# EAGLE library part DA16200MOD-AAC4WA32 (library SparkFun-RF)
Check prices

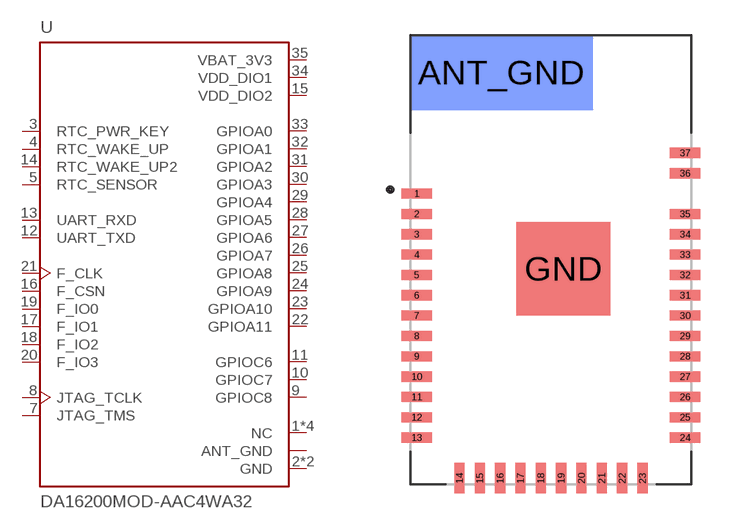
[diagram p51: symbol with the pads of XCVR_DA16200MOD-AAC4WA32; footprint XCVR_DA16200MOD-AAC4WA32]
Designator prefix U

## DA16200MOD-AAC4WA32 (PROD_ID: IC-16179; VALUE: DA16200MOD)  [XCVR_DA16200MOD-AAC4WA32]
1  NC  nc
2  GND  pwr
3  RTC_PWR_KEY  in
4  RTC_WAKE_UP  in
5  RTC_SENSOR  out
6  NC  nc
7  JTAG_TMS
8  JTAG_TCLK
9  GPIOC8
10  GPIOC7
11  GPIOC6
12  UART_TXD  out
13  UART_RXD  in
14  RTC_WAKE_UP2  in
15  VDD_DIO2  pwr
16  F_CSN
17  F_IO1
18  F_IO2
19  F_IO0
20  F_IO3
21  F_CLK
22  GPIOA11
23  GPIOA10
24  GPIOA9
25  GPIOA8
26  GPIOA7
27  GPIOA6
28  GPIOA5
29  GPIOA4
30  GPIOA3
31  GPIOA2
32  GPIOA1
33  GPIOA0
34  VDD_DIO1  pwr
35  VBAT_3V3  pwr
36  NC  nc
37  NC  nc
ANT_GND  ANT_GND  pwr
GND  GND  pwr

## Footprint XCVR_DA16200MOD-AAC4WA32 (pad centres in mm)
smd 1.5 x 0.5: 1 -6.6,3.25; 2 -6.6,2.25; 3 -6.6,1.25; 4 -6.6,0.25; 5 -6.6,-0.75; 6 -6.6,-1.75; 7 -6.6,-2.75; 8 -6.6,-3.75; 9 -6.6,-4.75; 10 -6.6,-5.75; 11 -6.6,-6.75; 12 -6.6,-7.75; 13 -6.6,-8.75; 24 6.6,-8.75; 25 6.6,-7.75; 26 6.6,-6.75; 27 6.6,-5.75; 28 6.6,-4.75; 29 6.6,-3.75; 30 6.6,-2.75; 31 6.6,-1.75; 32 6.6,-0.75; 33 6.6,0.25; 34 6.6,1.25; 35 6.6,2.25; 36 6.6,4.25; 37 6.6,5.25
smd 0.5 x 1.5: 14 -4.5,-10.75; 15 -3.5,-10.75; 16 -2.5,-10.75; 17 -1.5,-10.75; 18 -0.5,-10.75; 19 0.5,-10.75; 20 1.5,-10.75; 21 2.5,-10.75; 22 3.5,-10.75; 23 4.5,-10.75
smd 9 x 3.7 bottom: ANT_GND -2.45,9.2
smd 4.6 x 4.6: GND 0.61,-0.45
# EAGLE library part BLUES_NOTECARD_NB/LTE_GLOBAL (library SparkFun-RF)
Blues Wireless NoteCard NB/LTE - Global As an embeddable device-to-cloud data pump, the Notecard eliminates all complexity and friction that exists with existing IoT solutions. It enables development and rapid iteration of production-quality secure cellular or Wi-Fi IoT solutions at an extremely low, fixed cost. With as little as two lines of code on the controlling MCU, and with no external libraries or dependencies, data can be sent from device to cloud.

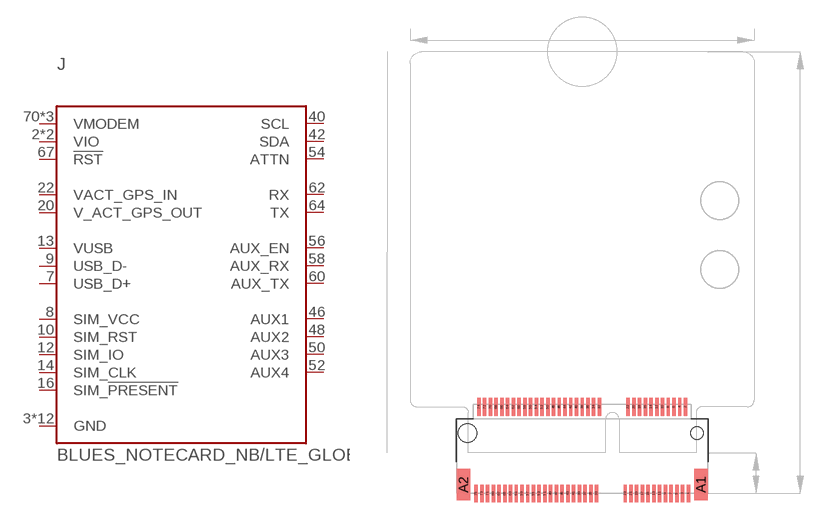
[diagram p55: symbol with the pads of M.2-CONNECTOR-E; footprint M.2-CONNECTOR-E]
Designator prefix J

## BLUES_NOTECARD_NB/LTE_GLOBAL (PROD_ID: CONN-14877; VALUE: Blues Notecard)  [M.2-CONNECTOR-E]
2  VIO
3  GND
4  VIO
5  GND
6  GND
7  USB_D+
8  SIM_VCC
9  USB_D-
10  SIM_RST
11  GND
12  SIM_IO
13  VUSB
14  SIM_CLK
16  SIM_!PRESENT!
18  GND
20  V_ACT_GPS_OUT
22  VACT_GPS_IN
33  GND
39  GND
40  SCL
42  SDA
45  GND
46  AUX1
48  AUX2
50  AUX3
51  GND
52  AUX4
54  ATTN
56  AUX_EN
57  GND
58  AUX_RX
60  AUX_TX
62  RX
64  TX
67  !RST!
70  VMODEM
71  GND
72  VMODEM
73  GND
74  VMODEM

## Footprint M.2-CONNECTOR-E (pad centres in mm)
smd 0.3 x 1.55: 1 9.25,-5.275; 2 9,2.275; 3 8.75,-5.275; 4 8.5,2.275; 5 8.25,-5.275; 6 8,2.275; 7 7.75,-5.275; 8 7.5,2.275; 9 7.25,-5.275; 10 7,2.275; 11 6.75,-5.275; 12 6.5,2.275; 13 6.25,-5.275; 14 6,2.275; 15 5.75,-5.275; 16 5.5,2.275; 17 5.25,-5.275; 18 5,2.275; 19 4.75,-5.275; 20 4.5,2.275; 21 4.25,-5.275; 22 4,2.275; 23 3.75,-5.275; 32 1.5,2.275; 33 1.25,-5.275; 34 1,2.275; 35 0.75,-5.275; 36 0.5,2.275; 37 0.25,-5.275; 38 0,2.275; 39 -0.25,-5.275; 40 -0.5,2.275; 41 -0.75,-5.275; 42 -1,2.275; 43 -1.25,-5.275; 44 -1.5,2.275; 45 -1.75,-5.275; 46 -2,2.275; 47 -2.25,-5.275; 48 -2.5,2.275; 49 -2.75,-5.275; 50 -3,2.275; 51 -3.25,-5.275; 52 -3.5,2.275; 53 -3.75,-5.275; 54 -4,2.275; 55 -4.25,-5.275; 56 -4.5,2.275; 57 -4.75,-5.275; 58 -5,2.275; 59 -5.25,-5.275; 60 -5.5,2.275; 61 -5.75,-5.275; 62 -6,2.275; 63 -6.25,-5.275; 64 -6.5,2.275; 65 -6.75,-5.275; 66 -7,2.275; 67 -7.25,-5.275; 68 -7.5,2.275; 69 -7.75,-5.275; 70 -8,2.275; 71 -8.25,-5.275; 72 -8.5,2.275; 73 -8.75,-5.275; 74 -9,2.275; 75 -9.25,-5.275
smd 1.2 x 2.75: A1 10.35,-4.5; A2 -10.35,-4.5
hole 1.1 at 10,0
hole 1.6 at -10,0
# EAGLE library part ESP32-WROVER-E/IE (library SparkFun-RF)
ESP32-WROVER-E/IE ESP32-WROVER-E uses the onboard antenna. ESP32-WROVER-IE has a u.FL antenna connector, but is otherwise the same as the -E. N16R8 has 16M Flash, 8M PSRAM

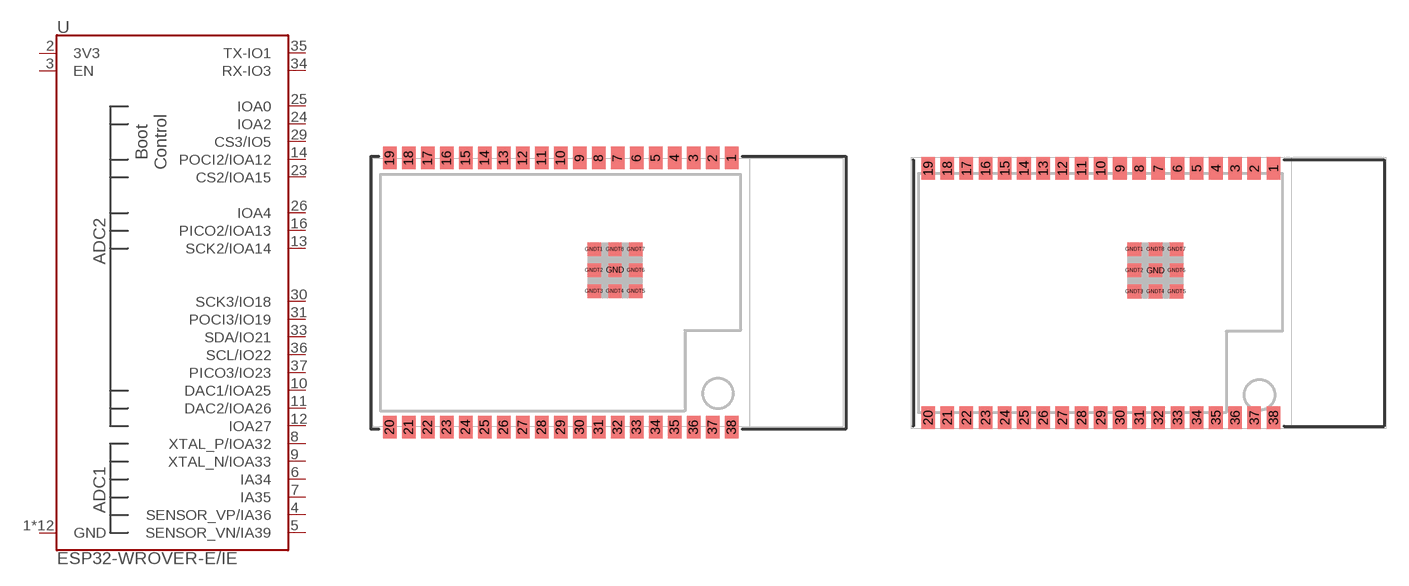
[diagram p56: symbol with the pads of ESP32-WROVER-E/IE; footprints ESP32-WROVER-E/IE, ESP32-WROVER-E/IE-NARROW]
Designator prefix U

## ESP32-WROVER-E/IE_IE-N16R8 (PROD_ID: IC-19265)  [ESP32-WROVER-E/IE]
1  GND
2  3V3
3  EN
4  SENSOR_VP/IA36
5  SENSOR_VN/IA39
6  IA34
7  IA35
8  XTAL_P/IOA32
9  XTAL_N/IOA33
10  DAC1/IOA25
11  DAC2/IOA26
12  IOA27
13  SCK2/IOA14
14  POCI2/IOA12
15  GND
16  PICO2/IOA13
23  CS2/IOA15
24  IOA2
25  IOA0
26  IOA4
29  CS3/IO5
30  SCK3/IO18
31  POCI3/IO19
33  SDA/IO21
34  RX-IO3
35  TX-IO1
36  SCL/IO22
37  PICO3/IO23
38  GND
GND  GND
GNDT1  GND
GNDT2  GND
GNDT3  GND
GNDT4  GND
GNDT5  GND
GNDT6  GND
GNDT7  GND
GNDT8  GND

## ESP32-WROVER-E/IE_IE-N16R8_NARROW (PROD_ID: IC-19265)  [ESP32-WROVER-E/IE-NARROW]
Pads as for ESP32-WROVER-E/IE

## Footprint ESP32-WROVER-E/IE (pad centres in mm)
ESP32-WROVER-E/IE ESP32-WROVER-E uses the onboard antenna. ESP32-WROVER-IE has a u.FL antenna connector, but is otherwise the same size as the -E.
smd 0.9 x 1.5: 1 7.8,9; 2 6.53,9; 3 5.26,9; 4 3.99,9; 5 2.72,9; 6 1.45,9; 7 0.18,9; 8 -1.09,9; 9 -2.36,9; 10 -3.63,9; 11 -4.9,9; 12 -6.17,9; 13 -7.44,9; 14 -8.71,9; 15 -9.98,9; 16 -11.25,9; 17 -12.52,9; 18 -13.79,9; 19 -15.06,9; 20 -15.06,-9; 21 -13.79,-9; 22 -12.52,-9; 23 -11.25,-9; 24 -9.98,-9; 25 -8.71,-9; 26 -7.44,-9; 27 -6.17,-9; 28 -4.9,-9; 29 -3.63,-9; 30 -2.36,-9; 31 -1.09,-9; 32 0.18,-9; 33 1.45,-9; 34 2.72,-9; 35 3.99,-9; 36 5.26,-9; 37 6.53,-9; 38 7.8,-9
smd 0.9 x 0.9: GND 0,1.5; GNDT1 -1.4,2.9; GNDT2 -1.4,1.5; GNDT3 -1.4,0.1; GNDT4 0,0.1; GNDT5 1.4,0.1; GNDT6 1.4,1.5; GNDT7 1.4,2.9; GNDT8 0,2.9

## Footprint ESP32-WROVER-E/IE-NARROW (pad centres in mm)
ESP32-WROVER-E/IE ESP32-WROVER-E uses the onboard antenna. ESP32-WROVER-IE has a u.FL antenna connector, but is otherwise the same size as the -E.
smd 0.9 x 1.5: 1 7.8,8.25; 2 6.53,8.25; 3 5.26,8.25; 4 3.99,8.25; 5 2.72,8.25; 6 1.45,8.25; 7 0.18,8.25; 8 -1.09,8.25; 9 -2.36,8.25; 10 -3.63,8.25; 11 -4.9,8.25; 12 -6.17,8.25; 13 -7.44,8.25; 14 -8.71,8.25; 15 -9.98,8.25; 16 -11.25,8.25; 17 -12.52,8.25; 18 -13.79,8.25; 19 -15.06,8.25; 20 -15.06,-8.25; 21 -13.79,-8.25; 22 -12.52,-8.25; 23 -11.25,-8.25; 24 -9.98,-8.25; 25 -8.71,-8.25; 26 -7.44,-8.25; 27 -6.17,-8.25; 28 -4.9,-8.25; 29 -3.63,-8.25; 30 -2.36,-8.25; 31 -1.09,-8.25; 32 0.18,-8.25; 33 1.45,-8.25; 34 2.72,-8.25; 35 3.99,-8.25; 36 5.26,-8.25; 37 6.53,-8.25; 38 7.8,-8.25
smd 0.9 x 0.9: GND 0,1.5; GNDT1 -1.4,2.9; GNDT2 -1.4,1.5; GNDT3 -1.4,0.1; GNDT4 0,0.1; GNDT5 1.4,0.1; GNDT6 1.4,1.5; GNDT7 1.4,2.9; GNDT8 0,2.9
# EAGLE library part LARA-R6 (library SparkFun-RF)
u-blox LARA-R6 single or multi-mode LTE Cat 1 modules

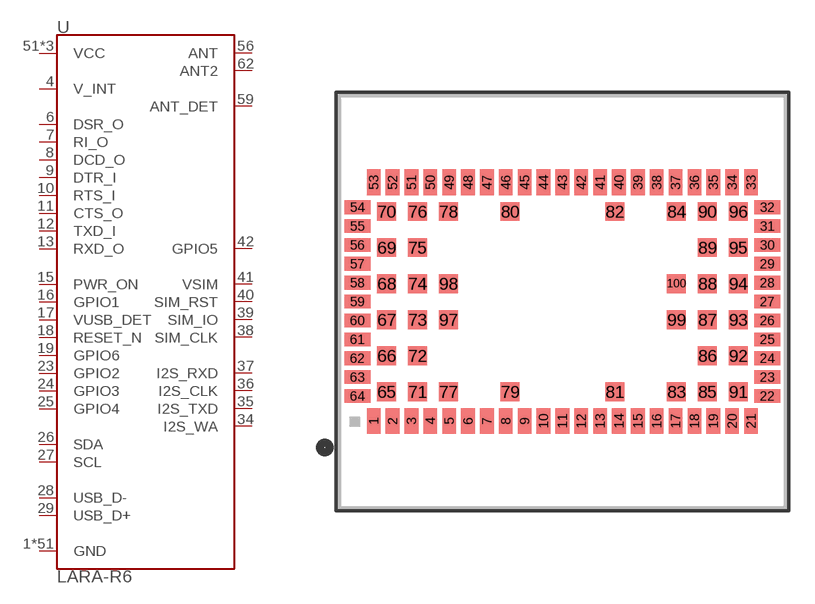
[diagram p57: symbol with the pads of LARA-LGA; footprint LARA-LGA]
Designator prefix U

## LARA-R6_R6001D_GLOBAL_DATA-ONLY (PROD_ID: IC-16661; VALUE: LARA-R6001D)  [LARA-LGA]
1  GND  pwr
3  GND  pwr
4  V_INT  out
5  GND  pwr
6  DSR_O  out
7  RI_O  out
8  DCD_O  out
9  DTR_I  in
10  RTS_I  in
11  CTS_O  out
12  TXD_I  in
13  RXD_O  out
14  GND  pwr
15  PWR_ON  in
16  GPIO1
17  VUSB_DET  in
18  RESET_N  in
19  GPIO6
20  GND  pwr
21  GND  pwr
22  GND  pwr
23  GPIO2
24  GPIO3
25  GPIO4
26  SDA
27  SCL
28  USB_D-
29  USB_D+
30  GND  pwr
32  GND  pwr
34  I2S_WA  out
35  I2S_TXD  out
36  I2S_CLK  out
37  I2S_RXD  in
38  SIM_CLK  out
39  SIM_IO
40  SIM_RST  out
41  VSIM  out
42  GPIO5
43  GND  pwr
50  GND  pwr
51  VCC  pwr
52  VCC  pwr
53  VCC  pwr
54  GND  pwr
55  GND  pwr
56  ANT
57  GND  pwr
58  GND  pwr
59  ANT_DET  in
60  GND  pwr
61  GND  pwr
62  ANT2
63  GND  pwr
64  GND  pwr
65  GND  pwr
66  GND  pwr
67  GND  pwr
68  GND  pwr
69  GND  pwr
70  GND  pwr
71  GND  pwr
72  GND  pwr
73  GND  pwr
74  GND  pwr
75  GND  pwr
76  GND  pwr
77  GND  pwr
78  GND  pwr
79  GND  pwr
80  GND  pwr
81  GND  pwr
82  GND  pwr
83  GND  pwr
84  GND  pwr
85  GND  pwr
86  GND  pwr
87  GND  pwr
88  GND  pwr
89  GND  pwr
90  GND  pwr
91  GND  pwr
92  GND  pwr
93  GND  pwr
94  GND  pwr
95  GND  pwr
96  GND  pwr

## LARA-R6_R6001_GLOBAL (PROD_ID: IC-17186; VALUE: LARA-R6001)  [LARA-LGA]
Pads as for LARA-LGA

## LARA-R6_R6401_USA (PROD_ID: IC-16756; VALUE: LARA-R6401)  [LARA-LGA]
Pads as for LARA-LGA

## Footprint LARA-LGA (pad centres in mm)
ublox LARA LGA form factor Miniature cellular modem package. Common form factor for many ublox cellular modules, including LARA-R6 series. Dimensions: 26.0 x 24.0 mm Pins: 100 Pitch: 1.1mm As per the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
smd 0.8 x 1.5: 1 -11,-6.95; 2 -9.9,-6.95; 3 -8.8,-6.95; 4 -7.7,-6.95; 5 -6.6,-6.95; 6 -5.5,-6.95; 7 -4.4,-6.95; 8 -3.3,-6.95; 9 -2.2,-6.95; 10 -1.1,-6.95; 11 0,-6.95; 12 1.1,-6.95; 13 2.2,-6.95; 14 3.3,-6.95; 15 4.4,-6.95; 16 5.5,-6.95; 17 6.6,-6.95; 18 7.7,-6.95; 19 8.8,-6.95; 20 9.9,-6.95; 21 11,-6.95; 33 11,6.95; 34 9.9,6.95; 35 8.8,6.95; 36 7.7,6.95; 37 6.6,6.95; 38 5.5,6.95; 39 4.4,6.95; 40 3.3,6.95; 41 2.2,6.95; 42 1.1,6.95; 43 0,6.95; 44 -1.1,6.95; 45 -2.2,6.95; 46 -3.3,6.95; 47 -4.4,6.95; 48 -5.5,6.95; 49 -6.6,6.95; 50 -7.7,6.95; 51 -8.8,6.95; 52 -9.9,6.95; 53 -11,6.95
smd 1.5 x 0.8: 22 11.95,-5.5; 23 11.95,-4.4; 24 11.95,-3.3; 25 11.95,-2.2; 26 11.95,-1.1; 27 11.95,0; 28 11.95,1.1; 29 11.95,2.2; 30 11.95,3.3; 31 11.95,4.4; 32 11.95,5.5; 54 -11.95,5.5; 55 -11.95,4.4; 56 -11.95,3.3; 57 -11.95,2.2; 58 -11.95,1.1; 59 -11.95,0; 60 -11.95,-1.1; 61 -11.95,-2.2; 62 -11.95,-3.3; 63 -11.95,-4.4; 64 -11.95,-5.5
smd 1.1 x 1.1: 65 -10.25,-5.25; 66 -10.25,-3.15; 67 -10.25,-1.05; 68 -10.25,1.05; 69 -10.25,3.15; 70 -10.25,5.25; 71 -8.45,-5.25; 72 -8.45,-3.15; 73 -8.45,-1.05; 74 -8.45,1.05; 75 -8.45,3.15; 76 -8.45,5.25; 77 -6.65,-5.25; 78 -6.65,5.25; 79 -3.05,-5.25; 80 -3.05,5.25; 81 3.05,-5.25; 82 3.05,5.25; 83 6.65,-5.25; 84 6.65,5.25; 85 8.45,-5.25; 86 8.45,-3.15; 87 8.45,-1.05; 88 8.45,1.05; 89 8.45,3.15; 90 8.45,5.25; 91 10.25,-5.25; 92 10.25,-3.15; 93 10.25,-1.05; 94 10.25,1.05; 95 10.25,3.15; 96 10.25,5.25; 97 -6.65,-1.05; 98 -6.65,1.05; 99 6.65,-1.05; 100 6.65,1.05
